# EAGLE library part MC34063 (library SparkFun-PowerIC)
Jellybean switching supply controller

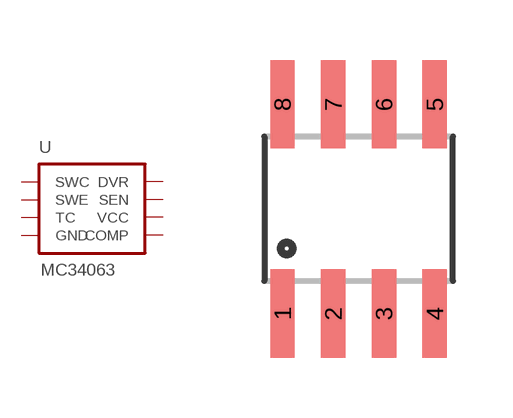
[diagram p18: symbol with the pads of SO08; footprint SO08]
Designator prefix U

## MC34063SMD  [SO08]
1  SWC
2  SWE
3  TC
4  GND
5  COMP
6  VCC
7  SEN
8  DVR

## Footprint SO08 (pad centres in mm)
Small Outline Package Fits JEDEC packages (narrow SOIC-8)
smd 0.61 x 2.21: 1 -1.905,-2.616; 2 -0.635,-2.616; 3 0.635,-2.616; 4 1.905,-2.616; 5 1.905,2.616; 6 0.635,2.616; 7 -0.635,2.616; 8 -1.905,2.616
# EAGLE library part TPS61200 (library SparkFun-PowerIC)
DC to DC Booster IC-10035

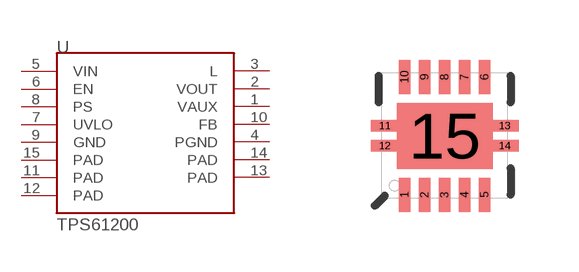
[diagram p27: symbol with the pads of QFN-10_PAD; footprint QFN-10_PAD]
Designator prefix U

## TPS61200 (PROD_ID: IC-10035)  [QFN-10_PAD]
1  VAUX  pas
2  VOUT  pas
3  L  pas
4  PGND  sup
5  VIN  sup
6  EN  in
7  UVLO  pas
8  PS  in
9  GND  sup
10  FB  pas
11  PAD  sup
12  PAD  sup
13  PAD  sup
14  PAD  sup
15  PAD  sup

## Footprint QFN-10_PAD (pad centres in mm)
smd 0.297 x 0.85: 1 -1,-1.475; 2 -0.5,-1.475; 3 0,-1.475; 4 0.5,-1.475; 5 1,-1.475; 6 1,1.475; 7 0.5,1.475; 8 0,1.475; 9 -0.5,1.475; 10 -1,1.475
smd 0.7 x 0.28: 11 -1.5,0.25; 12 -1.5,-0.25; 13 1.5,0.25; 14 1.5,-0.25
smd 2.4 x 1.65: 15 0,0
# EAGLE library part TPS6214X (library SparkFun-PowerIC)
3-17V, 2A Step Down Converter

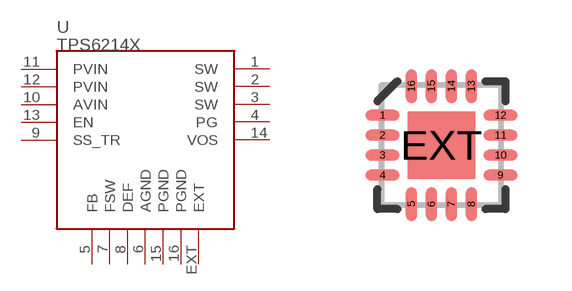
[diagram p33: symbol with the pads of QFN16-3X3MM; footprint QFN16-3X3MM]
Designator prefix U

## TPS6214X  [QFN16-3X3MM]
1  SW
2  SW
3  SW
4  PG
5  FB
6  AGND
7  FSW
8  DEF
9  SS_TR
10  AVIN
11  PVIN
12  PVIN
13  EN
14  VOS
15  PGND
16  PGND
EXT  EXT

## Footprint QFN16-3X3MM (pad centres in mm)
3mm x 3mm QFN 16 pin
smd 0.85 x 0.28: 1 -1.475,0.75; 2 -1.475,0.25; 3 -1.475,-0.25; 4 -1.475,-0.75; 9 1.475,-0.75; 10 1.475,-0.25; 11 1.475,0.25; 12 1.475,0.75
smd 0.28 x 0.85: 5 -0.75,-1.475; 6 -0.25,-1.475; 7 0.25,-1.475; 8 0.75,-1.475; 13 0.75,1.475; 14 0.25,1.475; 15 -0.25,1.475; 16 -0.75,1.475
smd 1.68 x 1.68: EXT 0,0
